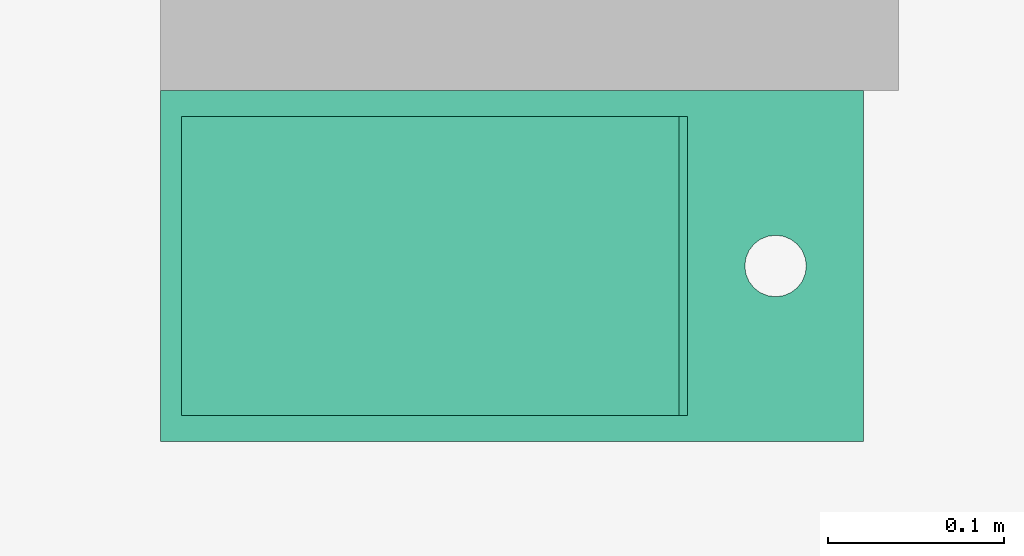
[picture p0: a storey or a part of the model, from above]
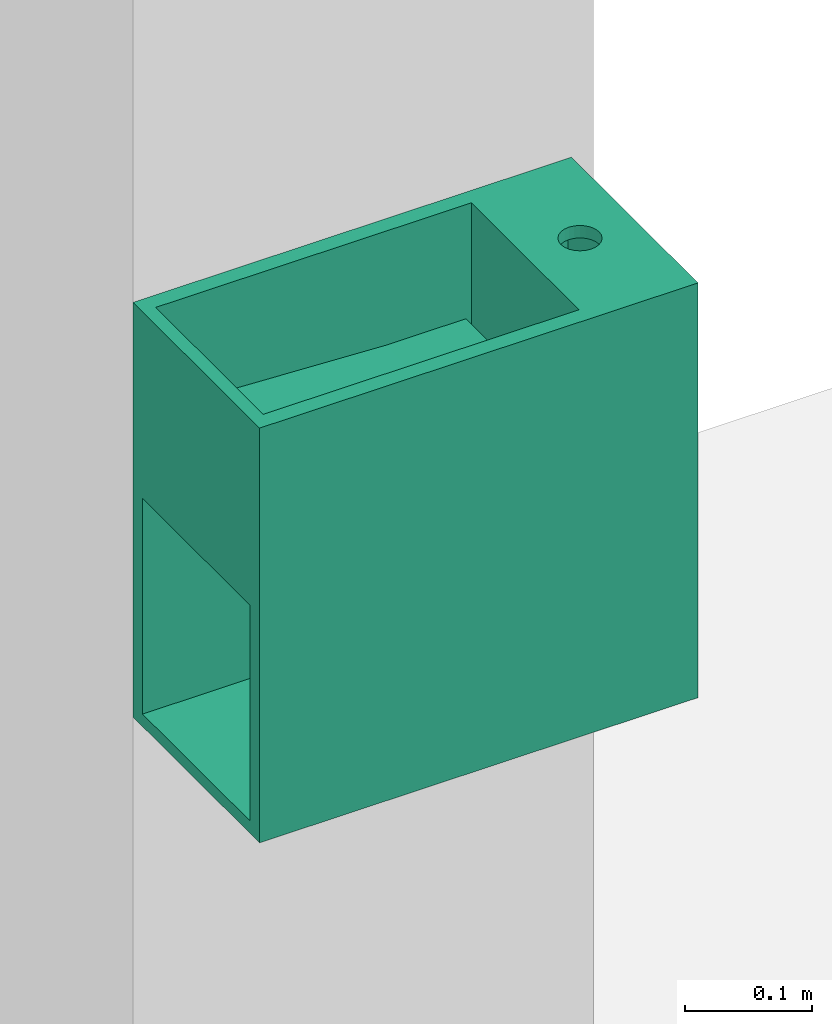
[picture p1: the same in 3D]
Properties of the parts of a building model (IFC2X3)

# File
Description: ViewDefinition [COBie2.4DesignDeliverable]
File name: Project Number
Time: 2023-04-13T08:58:37
Written by: The EXPRESS Data Manager Version 5.02.0100.07 : 28 Aug 2013
Made in: 20211019_1515(x64) - Exporter 20.2.60.15 - Alternate UI 20.2.60.15
Comment: STEP Physical File produced by: The EXPRESS Data Manager Version 5.02.0100.07 : 28 Aug 2013 * Module: EDMstepFileFactory/EDMstandAlone * Creation date: Thu Apr 13 08:58:37 2023 * Host: DESKTOP-KN3O7NT * Database: C:\Users\SARAHS~1\AppData\Local\Temp\afb68fbc-9b57-48e1-ba86-fc2cf789b9ff\64dbba90-2e63-4cdb-8aad-1c3831b28bef\ifc * Database version: 5507 * Database creation date: Thu Apr 13 08:58:37 2023 * Schema: IFC2X3 * Model: DataRepository.ifc * Model creation date: Thu Apr 13 08:58:37 2023 * Header model: DataRepository.ifc_HeaderModel * Header model creation date: Thu Apr 13 08:58:37 2023 * EDMuser: sdai-user * EDMgroup: sdai-group * License ID and type: 5605 : Permanent license. Expiry date: * EDMstepFileFactory options: 020000

# IfcProject, Project Number
LongName: Project Name; Phase: Awaiting Approval

# IfcSite, Default
RefLatitude: 51, 30, 23, 112487; RefLongitude: 0, -7, -37, -956022; RefElevation: 0 mm

# IfcBuilding, n/a
LongName: n/a
Pset_BuildingCommon - NumberOfStoreys: 1
Pset_ProductRequirements - Category: Project Information

# IfcBuildingStorey: Level:Circle Head - Project Datum, Level 0
In: n/a
LongName: Level 0; Elevation: 0 mm
Pset_AirSideSystemInformation - Name: Level 0
Pset_ProductRequirements - Name: Level 0; Category: Levels

# IfcFlowTerminal: DBLTD_Neilur_WallHungWashbasins_700340:Wall Mounted Basin, 17
In: Level 0
Classification: D2010 Plumbing Fixtures (Uniformat); Material: DBLTD_Neilur_SolidSurface_White
Pset_DistributionFlowElementCommon - Reference: Wall Mounted Basin; sets with these values: 2
Pset_ElementShading - Color: White
Pset_ManufacturerTypeInformation - ModelReference: Wall Mounted Basin; Manufacturer: https://www.neilur.com/
Pset_ProductRequirements - Name: Wall Mounted Basin; Category: Plumbing Fixtures
Plumbing Fixture Schedule - Family: DBLTD_Neilur_WallHungWashbasins_700340: Wall Mounted Basin; Manufacturer: https://www.neilur.com/; Model: 700340; Description: Wall Mounted Basin; Size: 400 x 200 x 400 mm

# IfcSlab: Floor:Floor-Grnd-Susp_65Scr-80Ins-100Blk-75PC, (4)
In: Level 0
Type - PredefinedType: FLOOR; Material: Concrete, Sand/Cement Screed 65 mm, Rigid insulation 80 mm, Air 150 mm, Concrete Masonry, Floor Block 100 mm, Concrete, Precast 75 mm
Type - Pset_ElementShading - Roughness: 914.4 mm
Type - Pset_ProductRequirements - Category: Floors
Type - Pset_QuantityTakeOff - Reference: Floor-Grnd-Susp_65Scr-80Ins-100Blk-75PC
Type - Pset_ReinforcementBarPitchOfSlab - Reference: Floor-Grnd-Susp_65Scr-80Ins-100Blk-75PC
Type - Pset_SlabCommon - Reference: Floor-Grnd-Susp_65Scr-80Ins-100Blk-75PC; IsExternal: no; ThermalTransmittance: 0.117438 kg/K/s3
Pset_QuantityTakeOff - sets with these values: 2
Pset_SlabCommon - LoadBearing: no; PitchAngle: 0 deg
BaseQuantities - GrossArea: 4 m2; NetArea: 11.76 m2; GrossVolume: 1880 m3; NetVolume: 1.88 m3; Perimeter: 8000 mm; Width: 470 mm

# IfcWallStandardCase: Basic Wall:Wall-Ext_102Bwk-75Ins-100LBlk-12P, (6)
In: Level 0
Type - PredefinedType: STANDARD; Material: Brick, Common 102.5 mm, Fiberglass Batt 75 mm, Concrete Masonry Units _Low Density 100 mm, Plaster 12.5 mm
Type - Pset_ElementShading - Roughness: 914.4 mm
Type - Pset_ProductRequirements - Category: Walls
Type - Pset_QuantityTakeOff - Reference: Wall-Ext_102Bwk-75Ins-100LBlk-12P
Type - Pset_ReinforcementBarPitchOfWall - Reference: Wall-Ext_102Bwk-75Ins-100LBlk-12P
Type - Pset_WallCommon - IsExternal: no; Reference: Wall-Ext_102Bwk-75Ins-100LBlk-12P; ThermalTransmittance: 0.235926 kg/K/s3
BaseQuantities - Height: 2000 mm; Length: 420 mm; Width: 290 mm; GrossFootprintArea: 0.1218 m2; NetVolume: 243600000 m3; NetSideArea: 840000 m2
Pset_QuantityTakeOff - sets with these values: 2
Pset_WallCommon - LoadBearing: no; IsExternal: yes; ExtendToStructure: no
